VERSION 5.8 ;
BUSBITCHARS "[]" ;
DIVIDERCHAR "/" ;
UNITS
    DATABASE MICRONS 1000 ;
END UNITS

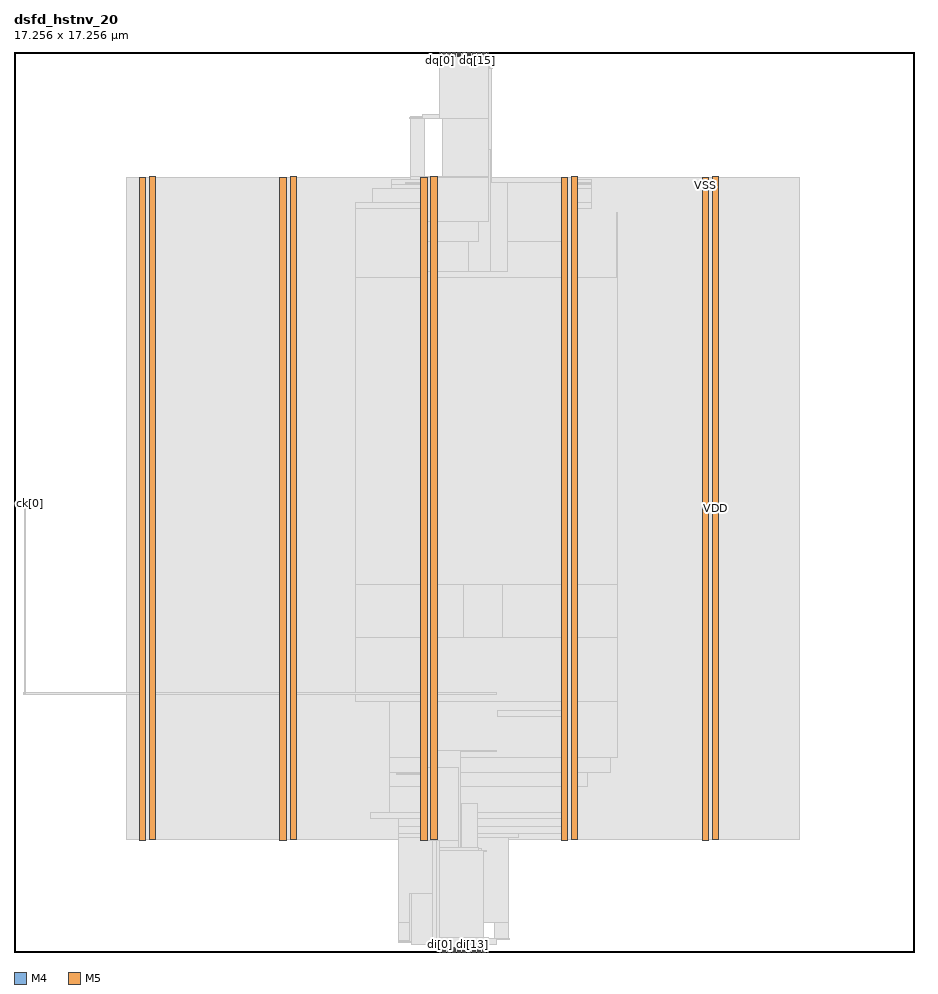
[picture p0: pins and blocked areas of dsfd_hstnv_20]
MACRO dsfd_hstnv_20
  FOREIGN dsfd_hstnv_20 0 0 ;
  CLASS BLOCK ;
  SIZE 17.256 BY 17.256 ;
  PIN ck[0]
    DIRECTION INPUT ;
    USE SIGNAL ;
    PORT
      LAYER M4 ;
        RECT  0 8.592 0.084 8.616 ;
    END
  END ck[0]
  PIN di[0]
    DIRECTION INPUT ;
    USE SIGNAL ;
    PORT
      LAYER M5 ;
        RECT  8.16 0 8.184 0.084 ;
    END
  END di[0]
  PIN di[10]
    DIRECTION INPUT ;
    USE SIGNAL ;
    PORT
      LAYER M5 ;
        RECT  8.64 0 8.664 0.084 ;
    END
  END di[10]
  PIN di[11]
    DIRECTION INPUT ;
    USE SIGNAL ;
    PORT
      LAYER M5 ;
        RECT  8.688 0 8.712 0.084 ;
    END
  END di[11]
  PIN di[12]
    DIRECTION INPUT ;
    USE SIGNAL ;
    PORT
      LAYER M5 ;
        RECT  8.736 0 8.76 0.084 ;
    END
  END di[12]
  PIN di[13]
    DIRECTION INPUT ;
    USE SIGNAL ;
    PORT
      LAYER M5 ;
        RECT  8.784 0 8.808 0.084 ;
    END
  END di[13]
  PIN di[14]
    DIRECTION INPUT ;
    USE SIGNAL ;
    PORT
      LAYER M5 ;
        RECT  8.832 0 8.856 0.084 ;
    END
  END di[14]
  PIN di[15]
    DIRECTION INPUT ;
    USE SIGNAL ;
    PORT
      LAYER M5 ;
        RECT  8.88 0 8.904 0.084 ;
    END
  END di[15]
  PIN di[16]
    DIRECTION INPUT ;
    USE SIGNAL ;
    PORT
      LAYER M5 ;
        RECT  8.928 0 8.952 0.084 ;
    END
  END di[16]
  PIN di[17]
    DIRECTION INPUT ;
    USE SIGNAL ;
    PORT
      LAYER M5 ;
        RECT  8.976 0 9 0.084 ;
    END
  END di[17]
  PIN di[18]
    DIRECTION INPUT ;
    USE SIGNAL ;
    PORT
      LAYER M5 ;
        RECT  9.024 0 9.048 0.084 ;
    END
  END di[18]
  PIN di[19]
    DIRECTION INPUT ;
    USE SIGNAL ;
    PORT
      LAYER M5 ;
        RECT  9.072 0 9.096 0.084 ;
    END
  END di[19]
  PIN di[1]
    DIRECTION INPUT ;
    USE SIGNAL ;
    PORT
      LAYER M5 ;
        RECT  8.208 0 8.232 0.084 ;
    END
  END di[1]
  PIN di[2]
    DIRECTION INPUT ;
    USE SIGNAL ;
    PORT
      LAYER M5 ;
        RECT  8.256 0 8.28 0.084 ;
    END
  END di[2]
  PIN di[3]
    DIRECTION INPUT ;
    USE SIGNAL ;
    PORT
      LAYER M5 ;
        RECT  8.304 0 8.328 0.084 ;
    END
  END di[3]
  PIN di[4]
    DIRECTION INPUT ;
    USE SIGNAL ;
    PORT
      LAYER M5 ;
        RECT  8.352 0 8.376 0.084 ;
    END
  END di[4]
  PIN di[5]
    DIRECTION INPUT ;
    USE SIGNAL ;
    PORT
      LAYER M5 ;
        RECT  8.4 0 8.424 0.084 ;
    END
  END di[5]
  PIN di[6]
    DIRECTION INPUT ;
    USE SIGNAL ;
    PORT
      LAYER M5 ;
        RECT  8.448 0 8.472 0.084 ;
    END
  END di[6]
  PIN di[7]
    DIRECTION INPUT ;
    USE SIGNAL ;
    PORT
      LAYER M5 ;
        RECT  8.496 0 8.52 0.084 ;
    END
  END di[7]
  PIN di[8]
    DIRECTION INPUT ;
    USE SIGNAL ;
    PORT
      LAYER M5 ;
        RECT  8.544 0 8.568 0.084 ;
    END
  END di[8]
  PIN di[9]
    DIRECTION INPUT ;
    USE SIGNAL ;
    PORT
      LAYER M5 ;
        RECT  8.592 0 8.616 0.084 ;
    END
  END di[9]
  PIN dq[0]
    DIRECTION OUTPUT ;
    USE SIGNAL ;
    PORT
      LAYER M5 ;
        RECT  8.16 17.172 8.184 17.256 ;
    END
  END dq[0]
  PIN dq[10]
    DIRECTION OUTPUT ;
    USE SIGNAL ;
    PORT
      LAYER M5 ;
        RECT  8.64 17.172 8.664 17.256 ;
    END
  END dq[10]
  PIN dq[11]
    DIRECTION OUTPUT ;
    USE SIGNAL ;
    PORT
      LAYER M5 ;
        RECT  8.688 17.172 8.712 17.256 ;
    END
  END dq[11]
  PIN dq[12]
    DIRECTION OUTPUT ;
    USE SIGNAL ;
    PORT
      LAYER M5 ;
        RECT  8.736 17.172 8.76 17.256 ;
    END
  END dq[12]
  PIN dq[13]
    DIRECTION OUTPUT ;
    USE SIGNAL ;
    PORT
      LAYER M5 ;
        RECT  8.784 17.172 8.808 17.256 ;
    END
  END dq[13]
  PIN dq[14]
    DIRECTION OUTPUT ;
    USE SIGNAL ;
    PORT
      LAYER M5 ;
        RECT  8.832 17.172 8.856 17.256 ;
    END
  END dq[14]
  PIN dq[15]
    DIRECTION OUTPUT ;
    USE SIGNAL ;
    PORT
      LAYER M5 ;
        RECT  8.88 17.172 8.904 17.256 ;
    END
  END dq[15]
  PIN dq[16]
    DIRECTION OUTPUT ;
    USE SIGNAL ;
    PORT
      LAYER M5 ;
        RECT  8.928 17.172 8.952 17.256 ;
    END
  END dq[16]
  PIN dq[17]
    DIRECTION OUTPUT ;
    USE SIGNAL ;
    PORT
      LAYER M5 ;
        RECT  8.976 17.172 9 17.256 ;
    END
  END dq[17]
  PIN dq[18]
    DIRECTION OUTPUT ;
    USE SIGNAL ;
    PORT
      LAYER M5 ;
        RECT  9.024 17.172 9.048 17.256 ;
    END
  END dq[18]
  PIN dq[19]
    DIRECTION OUTPUT ;
    USE SIGNAL ;
    PORT
      LAYER M5 ;
        RECT  9.072 17.172 9.096 17.256 ;
    END
  END dq[19]
  PIN dq[1]
    DIRECTION OUTPUT ;
    USE SIGNAL ;
    PORT
      LAYER M5 ;
        RECT  8.208 17.172 8.232 17.256 ;
    END
  END dq[1]
  PIN dq[2]
    DIRECTION OUTPUT ;
    USE SIGNAL ;
    PORT
      LAYER M5 ;
        RECT  8.256 17.172 8.28 17.256 ;
    END
  END dq[2]
  PIN dq[3]
    DIRECTION OUTPUT ;
    USE SIGNAL ;
    PORT
      LAYER M5 ;
        RECT  8.304 17.172 8.328 17.256 ;
    END
  END dq[3]
  PIN dq[4]
    DIRECTION OUTPUT ;
    USE SIGNAL ;
    PORT
      LAYER M5 ;
        RECT  8.352 17.172 8.376 17.256 ;
    END
  END dq[4]
  PIN dq[5]
    DIRECTION OUTPUT ;
    USE SIGNAL ;
    PORT
      LAYER M5 ;
        RECT  8.4 17.172 8.424 17.256 ;
    END
  END dq[5]
  PIN dq[6]
    DIRECTION OUTPUT ;
    USE SIGNAL ;
    PORT
      LAYER M5 ;
        RECT  8.448 17.172 8.472 17.256 ;
    END
  END dq[6]
  PIN dq[7]
    DIRECTION OUTPUT ;
    USE SIGNAL ;
    PORT
      LAYER M5 ;
        RECT  8.496 17.172 8.52 17.256 ;
    END
  END dq[7]
  PIN dq[8]
    DIRECTION OUTPUT ;
    USE SIGNAL ;
    PORT
      LAYER M5 ;
        RECT  8.544 17.172 8.568 17.256 ;
    END
  END dq[8]
  PIN dq[9]
    DIRECTION OUTPUT ;
    USE SIGNAL ;
    PORT
      LAYER M5 ;
        RECT  8.592 17.172 8.616 17.256 ;
    END
  END dq[9]
  PIN VDD
    DIRECTION INOUT ;
    USE POWER ;
    PORT
      LAYER M5 ;
        RECT  13.392 2.151 13.512 14.873 ;
        RECT  10.692 2.151 10.812 14.873 ;
        RECT  7.992 2.151 8.112 14.873 ;
        RECT  5.292 2.151 5.412 14.873 ;
        RECT  2.592 2.151 2.712 14.873 ;
    END
  END VDD
  PIN VSS
    DIRECTION INOUT ;
    USE GROUND ;
    PORT
      LAYER M5 ;
        RECT  13.2 2.137 13.32 14.859 ;
        RECT  10.5 2.137 10.62 14.859 ;
        RECT  7.8 2.137 7.92 14.859 ;
        RECT  5.1 2.137 5.22 14.859 ;
        RECT  2.4 2.137 2.52 14.859 ;
    END
  END VSS
  OBS
    LAYER RVTN ;
     RECT  2.16 2.16 15.066 2.295 ;
     RECT  2.16 2.565 15.066 2.835 ;
     RECT  2.16 3.105 15.066 3.375 ;
     RECT  2.16 3.645 15.066 3.915 ;
     RECT  2.16 4.185 15.066 4.455 ;
     RECT  2.16 4.725 15.066 4.995 ;
     RECT  2.16 5.265 15.066 5.535 ;
     RECT  2.16 5.805 15.066 6.075 ;
     RECT  2.16 6.345 15.066 6.615 ;
     RECT  2.16 6.885 15.066 7.155 ;
     RECT  2.16 7.425 15.066 7.695 ;
     RECT  2.16 7.965 15.066 8.235 ;
     RECT  2.16 8.505 15.066 8.775 ;
     RECT  2.16 9.045 15.066 9.315 ;
     RECT  2.16 9.585 15.066 9.855 ;
     RECT  2.16 10.125 15.066 10.395 ;
     RECT  2.16 10.665 15.066 10.935 ;
     RECT  2.16 11.205 15.066 11.475 ;
     RECT  2.16 11.745 15.066 12.015 ;
     RECT  2.16 12.285 15.066 12.555 ;
     RECT  2.16 12.825 15.066 13.095 ;
     RECT  2.16 13.365 15.066 13.635 ;
     RECT  2.16 13.905 15.066 14.175 ;
     RECT  2.16 14.445 15.066 14.715 ;
    LAYER RVTP ;
     RECT  2.16 2.295 15.066 2.565 ;
     RECT  2.16 2.835 15.066 3.105 ;
     RECT  2.16 3.375 15.066 3.645 ;
     RECT  2.16 3.915 15.066 4.185 ;
     RECT  2.16 4.455 15.066 4.725 ;
     RECT  2.16 4.995 15.066 5.265 ;
     RECT  2.16 5.535 15.066 5.805 ;
     RECT  2.16 6.075 15.066 6.345 ;
     RECT  2.16 6.615 15.066 6.885 ;
     RECT  2.16 7.155 15.066 7.425 ;
     RECT  2.16 7.695 15.066 7.965 ;
     RECT  2.16 8.235 15.066 8.505 ;
     RECT  2.16 8.775 15.066 9.045 ;
     RECT  2.16 9.315 15.066 9.585 ;
     RECT  2.16 9.855 15.066 10.125 ;
     RECT  2.16 10.395 15.066 10.665 ;
     RECT  2.16 10.935 15.066 11.205 ;
     RECT  2.16 11.475 15.066 11.745 ;
     RECT  2.16 12.015 15.066 12.285 ;
     RECT  2.16 12.555 15.066 12.825 ;
     RECT  2.16 13.095 15.066 13.365 ;
     RECT  2.16 13.635 15.066 13.905 ;
     RECT  2.16 14.175 15.066 14.445 ;
     RECT  2.16 14.715 15.066 14.85 ;
    LAYER M1 ;
     RECT  2.16 2.151 15.066 14.859 ;
    LAYER M2 ;
     RECT  2.16 2.151 7.735 14.859 ;
     RECT  7.735 2.106 8.375 14.859 ;
     RECT  8.375 2.151 15.066 14.859 ;
    LAYER M3 ;
     RECT  7.632 0.139 7.65 0.187 ;
     RECT  9.216 0.139 9.234 0.235 ;
     RECT  7.38 0.187 7.65 0.571 ;
     RECT  9.216 0.235 9.486 0.571 ;
     RECT  7.38 0.571 9.486 2.191 ;
     RECT  7.38 2.191 9.666 2.263 ;
     RECT  10.515 2.143 10.605 2.263 ;
     RECT  2.415 2.143 2.505 2.413 ;
     RECT  5.115 2.143 5.205 2.413 ;
     RECT  7.38 2.263 10.605 2.413 ;
     RECT  13.215 2.143 13.305 2.413 ;
     RECT  7.38 2.413 10.797 2.569 ;
     RECT  6.84 2.569 10.797 2.669 ;
     RECT  7.2 2.669 10.797 3.181 ;
     RECT  7.2 3.181 10.998 3.451 ;
     RECT  7.2 3.451 11.43 3.721 ;
     RECT  7.2 3.721 11.574 4.801 ;
     RECT  6.552 4.801 11.574 6.035 ;
     RECT  6.552 6.035 8.622 7.051 ;
     RECT  9.36 6.035 11.574 7.051 ;
     RECT  6.552 7.051 11.574 12.929 ;
     RECT  11.556 12.929 11.574 14.171 ;
     RECT  6.552 12.929 10.797 14.251 ;
     RECT  6.552 14.251 11.07 14.369 ;
     RECT  2.415 2.413 2.697 14.597 ;
     RECT  5.115 2.413 5.397 14.597 ;
     RECT  13.215 2.413 13.497 14.597 ;
     RECT  6.876 14.369 11.07 14.639 ;
     RECT  7.236 14.639 9.486 14.711 ;
     RECT  10.368 14.639 11.07 14.711 ;
     RECT  7.236 14.711 9.162 14.819 ;
     RECT  10.707 14.711 11.07 14.819 ;
     RECT  7.596 14.819 9.162 14.861 ;
     RECT  2.607 14.597 2.697 14.867 ;
     RECT  5.307 14.597 5.397 14.867 ;
     RECT  7.596 14.861 8.097 14.867 ;
     RECT  10.707 14.819 10.797 14.867 ;
     RECT  13.407 14.597 13.497 14.867 ;
     RECT  7.596 14.867 7.866 16.013 ;
     RECT  7.848 16.013 7.866 16.061 ;
     RECT  8.856 14.861 9.162 16.973 ;
     RECT  8.856 16.973 9.09 17.069 ;
     RECT  9.072 17.069 9.09 17.117 ;
    LAYER M4 ;
     RECT  0.06 8.592 0.227 8.616 ;
     RECT  0.181 4.944 2.408 4.968 ;
     RECT  2.408 2.148 2.512 14.592 ;
     RECT  2.512 2.418 2.6 14.592 ;
     RECT  2.6 2.418 2.704 14.862 ;
     RECT  2.704 4.944 5.108 4.968 ;
     RECT  5.108 2.148 5.212 14.592 ;
     RECT  5.212 2.418 5.3 14.592 ;
     RECT  5.3 2.418 5.404 14.862 ;
     RECT  7.369 0.192 7.585 0.216 ;
     RECT  7.585 0.192 7.621 1.128 ;
     RECT  7.333 3.408 7.808 3.432 ;
     RECT  5.404 4.944 7.808 4.968 ;
     RECT  7.513 14.736 7.808 14.76 ;
     RECT  7.585 15.984 7.837 16.008 ;
     RECT  7.808 2.148 8 14.76 ;
     RECT  7.621 0.144 8.017 1.128 ;
     RECT  8 2.148 8.017 14.862 ;
     RECT  8.017 0.144 8.104 14.862 ;
     RECT  7.837 15.984 8.339 16.056 ;
     RECT  8.104 13.056 8.533 14.862 ;
     RECT  8.104 0.144 8.561 3.864 ;
     RECT  8.561 0.144 8.579 2.856 ;
     RECT  8.579 0.144 8.723 0.6 ;
     RECT  8.629 16.848 8.845 16.872 ;
     RECT  8.579 1.728 8.885 2.856 ;
     RECT  8.885 1.776 8.957 1.992 ;
     RECT  8.845 16.848 8.963 17.064 ;
     RECT  8.957 1.776 8.993 1.944 ;
     RECT  8.963 16.944 9.013 17.064 ;
     RECT  8.993 1.92 9.065 1.944 ;
     RECT  9.013 16.944 9.101 17.112 ;
     RECT  8.533 13.056 9.137 15.384 ;
     RECT  9.101 16.944 9.173 16.968 ;
     RECT  8.723 0.144 9.245 0.264 ;
     RECT  8.561 3.84 9.245 3.864 ;
     RECT  8.104 4.944 9.245 4.968 ;
     RECT  9.137 13.056 9.461 14.76 ;
     RECT  9.245 0.24 9.497 0.264 ;
     RECT  9.277 4.512 10.508 4.632 ;
     RECT  9.461 13.632 10.508 14.76 ;
     RECT  10.508 2.148 10.612 14.76 ;
     RECT  10.612 2.418 10.7 14.76 ;
     RECT  10.7 2.418 10.804 14.862 ;
     RECT  10.804 14.736 11.081 14.76 ;
     RECT  13.208 2.148 13.312 14.592 ;
     RECT  13.312 2.418 13.4 14.592 ;
     RECT  13.4 2.418 13.504 14.862 ;
    LAYER M5 ;
     RECT  8.16 0.016 9.096 0.275 ;
     RECT  8.16 0.275 9 1.955 ;
     RECT  8.16 1.955 8.904 2.003 ;
     RECT  8.16 2.003 8.52 2.137 ;
     RECT  2.4 2.137 2.52 2.151 ;
     RECT  5.1 2.137 5.22 2.151 ;
     RECT  10.5 2.137 10.62 2.151 ;
     RECT  13.2 2.137 13.32 2.151 ;
     RECT  7.8 2.137 8.52 3.539 ;
     RECT  0.192 4.933 0.216 8.627 ;
     RECT  7.8 3.539 8.112 13.045 ;
     RECT  7.8 13.045 8.712 13.621 ;
     RECT  7.8 13.621 8.904 14.005 ;
     RECT  2.4 2.151 2.712 14.859 ;
     RECT  5.1 2.151 5.412 14.859 ;
     RECT  7.8 14.005 9.096 14.859 ;
     RECT  10.5 2.151 10.812 14.859 ;
     RECT  13.2 2.151 13.512 14.859 ;
     RECT  2.592 14.859 2.712 14.873 ;
     RECT  5.292 14.859 5.412 14.873 ;
     RECT  7.992 14.859 9.096 14.873 ;
     RECT  10.692 14.859 10.812 14.873 ;
     RECT  13.392 14.859 13.512 14.873 ;
     RECT  8.208 14.873 9.096 15.973 ;
     RECT  8.16 15.973 9.096 17.232 ;
  END
END dsfd_hstnv_20
END LIBRARY
